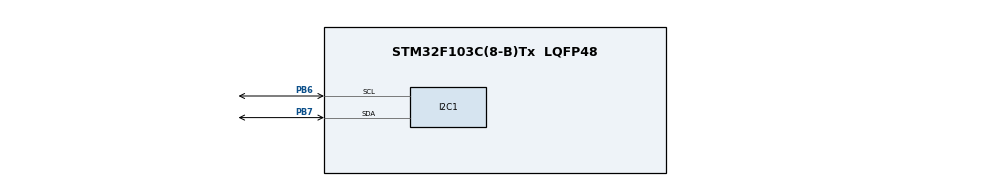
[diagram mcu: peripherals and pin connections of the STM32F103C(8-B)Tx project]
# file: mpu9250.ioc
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I2C1.I2C_Mode=I2C_Standard
I2C1.OwnAddress=0x69
Mcu.Family=STM32F1
Mcu.Name=STM32F103C(8-B)Tx
Mcu.Package=LQFP48
NVIC.PriorityGroup=NVIC_PRIORITYGROUP_4
PB6.Mode=I2C
PB6.Signal=I2C1_SCL
PB7.Mode=I2C
PB7.Signal=I2C1_SDA
ProjectManager.HeapSize=0x200
ProjectManager.StackSize=0x400
ProjectManager.TargetToolchain=STM32CubeIDE
RCC.APB1Freq_Value=8000000
RCC.APB2Freq_Value=8000000
VP_SYS_VS_ND.Mode=No_Debug
board=custom

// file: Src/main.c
/* USER CODE BEGIN Header */
/**
  ******************************************************************************
  * @file           : main.c
  * @brief          : Main program body
  ******************************************************************************
  * @attention
  *
  * <h2><center>&copy; Copyright (c) 2020 STMicroelectronics.
  * All rights reserved.</center></h2>
  *
  * This software component is licensed by ST under BSD 3-Clause license,
  * the "License"; You may not use this file except in compliance with the
  * License. You may obtain a copy of the License at:
  *                        opensource.org/licenses/BSD-3-Clause
  *
  ******************************************************************************
  */
/* USER CODE END Header */

#include "main.h"
#include "i2c.h"
#include "usb_device.h"
#include "gpio.h"

/* USER CODE BEGIN Includes */
#include "mpu9250.h"
#include "usbd_cdc_if.h"
#include <string.h>
#include <pid.h>

/* USER CODE END Includes */

void SystemClock_Config(void);
/* USER CODE BEGIN PFP */
void test_success(void);
void test_failed(void);
void print_float_usb(float number);

/* USER CODE END PFP */

int main(void)
{
  /* USER CODE BEGIN 1 */
  struct MPU9250_Handle_s MPU9250_Handle;
  PID_Handle_t hpid1;

  /* USER CODE END 1 */

  /* MCU Configuration--------------------------------------------------------*/

  /* Reset of all peripherals, Initializes the Flash interface and the Systick. */
  HAL_Init();

  /* Configure the system clock */
  SystemClock_Config();

  /* Initialize all configured peripherals */
  MX_GPIO_Init();
  MX_I2C1_Init();
  MX_USB_DEVICE_Init();
  /* USER CODE BEGIN 2 */

  int i = 0;
  while (MPU9250_begin(&MPU9250_Handle) < 0) {
	  i++;
	  if (i > 2) {
		  test_failed();
		  while(1)
			  ;
	  }
  }

  i = 0;
  while (MPU9250_readSensor(&MPU9250_Handle) < 0) {
	  i++;
	  if (i > 2) {
		  test_failed();
		  while(1)
			  ;
	  }
  }

  test_success();

  PID_Config(&hpid1, 1.0, 1.0, 0.0, 0.02, 20.0);
  PID_Init(&hpid1);

  /* USER CODE END 2 */

  /* Infinite loop */
  while (1)
  {

    /* USER CODE BEGIN 3 */
	  if(MPU9250_readSensor(&MPU9250_Handle) > 0) {

		  print_float_usb(MPU9250_getAccelX_mss(&MPU9250_Handle));
		  print_float_usb(MPU9250_getAccelY_mss(&MPU9250_Handle));
		  print_float_usb(MPU9250_getAccelZ_mss(&MPU9250_Handle));

		  print_float_usb(MPU9250_getGyroX_rads(&MPU9250_Handle));
	  	  print_float_usb(MPU9250_getGyroY_rads(&MPU9250_Handle));
	  	  print_float_usb(MPU9250_getGyroZ_rads(&MPU9250_Handle));

	  	  print_float_usb(MPU9250_getMagX_uT(&MPU9250_Handle));
	  	  print_float_usb(MPU9250_getMagY_uT(&MPU9250_Handle));
	  	  print_float_usb(MPU9250_getMagZ_uT(&MPU9250_Handle));

	  	  print_float_usb(MPU9250_getTemperature_C(&MPU9250_Handle));

	  	  print_float_usb(PID_Regulate(&hpid1, -9.31, MPU9250_getAccelZ_mss(&MPU9250_Handle)));
	  }
  }
  /* USER CODE END 3 */
}

void SystemClock_Config(void)
{
  RCC_OscInitTypeDef RCC_OscInitStruct = {0};
  RCC_ClkInitTypeDef RCC_ClkInitStruct = {0};
  RCC_PeriphCLKInitTypeDef PeriphClkInit = {0};

  /** Initializes the CPU, AHB and APB busses clocks
  */
  RCC_OscInitStruct.OscillatorType = RCC_OSCILLATORTYPE_HSE;
  RCC_OscInitStruct.HSEState = RCC_HSE_ON;
  RCC_OscInitStruct.HSEPredivValue = RCC_HSE_PREDIV_DIV1;
  RCC_OscInitStruct.HSIState = RCC_HSI_ON;
  RCC_OscInitStruct.PLL.PLLState = RCC_PLL_ON;
  RCC_OscInitStruct.PLL.PLLSource = RCC_PLLSOURCE_HSE;
  RCC_OscInitStruct.PLL.PLLMUL = RCC_PLL_MUL6;
  if (HAL_RCC_OscConfig(&RCC_OscInitStruct) != HAL_OK)
  {
    Error_Handler();
  }
  /** Initializes the CPU, AHB and APB busses clocks
  */
  RCC_ClkInitStruct.ClockType = RCC_CLOCKTYPE_HCLK|RCC_CLOCKTYPE_SYSCLK
                              |RCC_CLOCKTYPE_PCLK1|RCC_CLOCKTYPE_PCLK2;
  RCC_ClkInitStruct.SYSCLKSource = RCC_SYSCLKSOURCE_PLLCLK;
  RCC_ClkInitStruct.AHBCLKDivider = RCC_SYSCLK_DIV1;
  RCC_ClkInitStruct.APB1CLKDivider = RCC_HCLK_DIV2;
  RCC_ClkInitStruct.APB2CLKDivider = RCC_HCLK_DIV1;

  if (HAL_RCC_ClockConfig(&RCC_ClkInitStruct, FLASH_LATENCY_1) != HAL_OK)
  {
    Error_Handler();
  }
  PeriphClkInit.PeriphClockSelection = RCC_PERIPHCLK_USB;
  PeriphClkInit.UsbClockSelection = RCC_USBCLKSOURCE_PLL;
  if (HAL_RCCEx_PeriphCLKConfig(&PeriphClkInit) != HAL_OK)
  {
    Error_Handler();
  }
}

/* USER CODE BEGIN 4 */

void print_float_usb(float number) {

	while (CDC_Transmit_FS((uint8_t *)&number, sizeof(float)) != USBD_OK);
}

void test_success(void) {
	// Turn on LED
	HAL_GPIO_WritePin(LED_GPIO_Port, LED_Pin, GPIO_PIN_RESET);
}

void test_failed(void) {
	// Turn off LED
	HAL_GPIO_WritePin(LED_GPIO_Port, LED_Pin, GPIO_PIN_SET);
}

/* USER CODE END 4 */

void Error_Handler(void)
{
}

/************************ (C) COPYRIGHT STMicroelectronics *****END OF FILE****/
